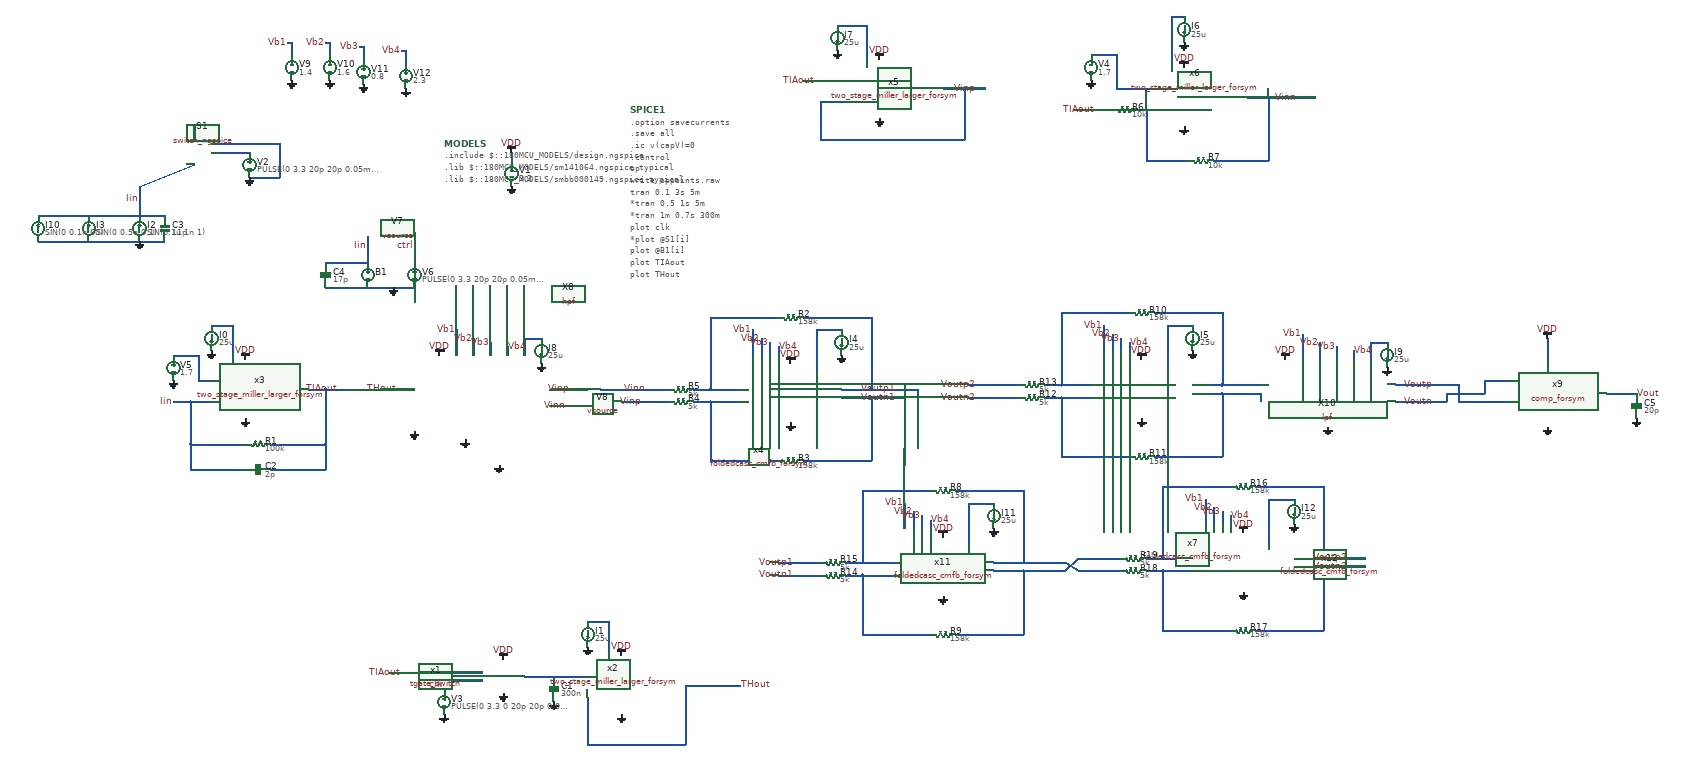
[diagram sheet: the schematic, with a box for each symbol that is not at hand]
v {xschem version=3.4.8RC file_version=1.3}
G {}
K {}
V {}
S {}
F {}
E {}
N 870 110 940 110 {lab=#net1
}
N 940 110 1020 110 {lab=#net1
}
N 1020 160 1020 270 {lab=THout
}
N 1250 130 1250 270 {lab=THout
}
N 1020 270 1250 270 {lab=THout
}
N 680 100 770 100 {lab=TIAout
}
N 680 120 770 120 {lab=clk
}
N 840 -1130 840 -1110 {lab=VDD}
N 680 120 680 140 {lab=clk
}
N 550 100 680 100 {lab=TIAout
}
N 360 -570 400 -570 {lab=TIAout
}
N 130 -720 180 -720 {lab=#net2
}
N 180 -720 180 -650 {lab=#net2
}
N 400 -570 400 -440 {lab=TIAout
}
N 80 -540 80 -440 {lab=Iin
}
N 80 -540 130 -540 {lab=Iin
}
N 270 -440 400 -440 {lab=TIAout
}
N 80 -440 210 -440 {lab=Iin
}
N 270 -380 400 -380 {lab=TIAout
}
N 400 -440 400 -380 {lab=TIAout
}
N 80 -380 210 -380 {lab=Iin
}
N 80 -440 80 -380 {lab=Iin
}
N 400 -570 450 -570 {lab=TIAout
}
N 40 -540 80 -540 {lab=Iin
}
N 40 -650 100 -650 {lab=#net3
}
N 100 -650 100 -590 {lab=#net3
}
N 100 -590 130 -590 {lab=#net3
}
N -40 -1010 -40 -980 {lab=Iin
spice_ignore=true}
N -40 -980 20 -980 {lab=Iin
spice_ignore=true}
N -40 -920 20 -920 {lab=0
spice_ignore=true}
N 1250 130 1380 130 {lab=THout
}
N 1020 -20 1070 -20 {lab=#net4
}
N 1070 -20 1070 50 {lab=#net4
}
N -40 -1050 -40 -1010 {lab=Iin
spice_ignore=true}
N 130 -1130 220 -1130 {lab=#net3
spice_ignore=true}
N 130 -1150 290 -1150 {lab=0
spice_ignore=true}
N 220 -1070 290 -1070 {lab=0
spice_ignore=true}
N 290 -1150 290 -1070 {lab=0
spice_ignore=true}
N -160 -980 -40 -980 {lab=Iin
spice_ignore=true}
N -160 -920 -40 -920 {lab=0
spice_ignore=true}
N -40 -1050 90 -1100 {lab=Iin
spice_ignore=true}
N 90 -1190 90 -1160 {lab=#net4
spice_ignore=true}
N 1620 -550 1690 -550 {lab=Voutn1
}
N 1690 -550 1690 -400 {lab=Voutn1
}
N 1310 -540 1380 -540 {lab=#net5
}
N 1310 -570 1380 -570 {lab=#net6
}
N 1310 -740 1310 -590 {lab=#net6
}
N 1620 -570 1690 -570 {lab=Voutp1
}
N 1690 -740 1690 -570 {lab=Voutp1
}
N 1690 -570 1800 -570 {lab=Voutp1
}
N 1690 -550 1770 -550 {lab=Voutn1
}
N 1410 -710 1410 -650 {lab=Vb1
}
N 1430 -690 1430 -650 {lab=Vb2
}
N 1530 -740 1690 -740 {lab=Voutp1
}
N 1310 -740 1470 -740 {lab=#net6
}
N 1530 -400 1690 -400 {lab=Voutn1
}
N 1310 -400 1470 -400 {lab=#net5
}
N 1270 -570 1310 -570 {lab=#net6
}
N 1270 -540 1310 -540 {lab=#net5
}
N 1310 -590 1310 -570 {lab=#net6
}
N 1310 -540 1310 -400 {lab=#net5
}
N 1450 -680 1450 -650 {lab=Vb3
}
N 1470 -670 1470 -650 {lab=Vb4
}
N 1560 -710 1560 -610 {lab=#net7
}
N 1560 -710 1620 -710 {lab=#net7
}
N 1800 -570 1800 -550 {lab=Voutp1
}
N 1770 -580 1770 -550 {lab=Voutn1
}
N 2450 -560 2520 -560 {lab=#net8
}
N 2520 -560 2520 -410 {lab=#net8
}
N 2140 -550 2210 -550 {lab=#net9
}
N 2140 -580 2210 -580 {lab=#net10
}
N 2140 -750 2140 -600 {lab=#net10
}
N 2450 -580 2520 -580 {lab=#net11
}
N 2520 -750 2520 -580 {lab=#net11
}
N 2240 -720 2240 -660 {lab=Vb1
}
N 2260 -700 2260 -660 {lab=Vb2
}
N 2360 -750 2520 -750 {lab=#net11
}
N 2140 -750 2300 -750 {lab=#net10
}
N 2360 -410 2520 -410 {lab=#net8
}
N 2140 -410 2300 -410 {lab=#net9
}
N 2100 -580 2140 -580 {lab=#net10
}
N 2100 -550 2140 -550 {lab=#net9
}
N 2000 -550 2040 -550 {lab=Voutn2
}
N 2140 -600 2140 -580 {lab=#net10
}
N 2140 -550 2140 -410 {lab=#net9
}
N 2280 -690 2280 -660 {lab=Vb3
}
N 2300 -680 2300 -660 {lab=Vb4
}
N 2390 -720 2390 -620 {lab=#net12
}
N 2390 -720 2450 -720 {lab=#net12
}
N 2000 -580 2040 -580 {lab=Voutp2
}
N 2520 -580 2610 -580 {lab=#net11
}
N 2520 -560 2610 -560 {lab=#net8
}
N 1920 -580 2000 -580 {lab=Voutp2
}
N 1920 -550 2000 -550 {lab=Voutn2
}
N 320 -1390 320 -1360 {lab=Vb1
}
N 310 -1390 320 -1390 {lab=Vb1
}
N 410 -1390 410 -1360 {lab=Vb2
}
N 400 -1390 410 -1390 {lab=Vb2
}
N 490 -1380 490 -1350 {lab=Vb3
}
N 480 -1380 490 -1380 {lab=Vb3
}
N 590 -1370 590 -1340 {lab=Vb4
}
N 580 -1370 590 -1370 {lab=Vb4
}
N 1530 -1300 1630 -1300 {lab=TIAout
spice_ignore=true}
N 1570 -1250 1630 -1250 {lab=Vinp
spice_ignore=true}
N 1570 -1250 1570 -1160 {lab=Vinp
spice_ignore=true}
N 1570 -1160 1910 -1160 {lab=Vinp
spice_ignore=true}
N 1910 -1280 1910 -1160 {lab=Vinp
spice_ignore=true}
N 1860 -1280 1910 -1280 {lab=Vinp
spice_ignore=true}
N 2580 -1260 2740 -1260 {lab=Vinn
spice_ignore=true}
N 1610 -1430 1680 -1430 {lab=#net11
spice_ignore=true}
N 1680 -1430 1680 -1350 {lab=#net11
spice_ignore=true}
N 2400 -1450 2400 -1340 {lab=#net12
spice_ignore=true}
N 2400 -1450 2430 -1450 {lab=#net12
spice_ignore=true}
N 1910 -1280 1960 -1280 {lab=Vinp
spice_ignore=true}
N 2310 -1280 2350 -1280 {lab=#net13
spice_ignore=true}
N 2310 -1230 2350 -1230 {lab=#net14
spice_ignore=true}
N 2270 -1280 2310 -1280 {lab=#net13
spice_ignore=true}
N 2630 -1260 2630 -1110 {lab=Vinn
spice_ignore=true}
N 2500 -1110 2630 -1110 {lab=Vinn
spice_ignore=true}
N 2340 -1110 2440 -1110 {lab=#net14
spice_ignore=true}
N 2340 -1230 2340 -1110 {lab=#net14
spice_ignore=true}
N 2170 -1230 2260 -1230 {lab=TIAout
spice_ignore=true}
N 2210 -1360 2270 -1360 {lab=#net13
spice_ignore=true}
N 2270 -1360 2270 -1280 {lab=#net13
spice_ignore=true}
N 1100 -570 1210 -570 {lab=Vinn
}
N 1100 -540 1210 -540 {lab=Vinp
}
N 500 -810 610 -810 {lab=0
}
N 610 -940 610 -870 {lab=ctrl
}
N 500 -930 500 -870 {lab=Iin
}
N 400 -870 500 -870 {lab=Iin
}
N 400 -810 500 -810 {lab=0
}
N 1050 -570 1100 -570 {lab=Vinn}
N 2930 -580 2980 -580 {lab=Voutp}
N 2930 -540 2980 -540 {lab=Voutn}
N 2980 -580 3050 -580 {lab=Voutp}
N 2980 -540 3050 -540 {lab=Voutn}
N 3290 -690 3290 -630 {lab=VDD}
N 3430 -560 3500 -560 {lab=Vout}
N 3140 -590 3200 -590 {lab=Voutn}
N 3120 -540 3200 -540 {lab=Voutp}
N 3140 -590 3140 -570 {lab=Voutn}
N 3080 -540 3120 -540 {lab=Voutp}
N 3050 -580 3080 -580 {lab=Voutp}
N 3080 -580 3080 -540 {lab=Voutp}
N 3050 -560 3050 -540 {lab=Voutn}
N 3050 -560 3140 -560 {lab=Voutn}
N 3140 -570 3140 -560 {lab=Voutn}
N 530 -570 610 -570 {lab=THout}
N 930 -570 1020 -570 {lab=Vinp}
N 930 -530 1010 -530 {lab=Vinn}
N 710 -710 710 -650 {lab=Vb1
}
N 750 -690 750 -650 {lab=Vb2
}
N 790 -680 790 -650 {lab=Vb3
}
N 830 -670 830 -650 {lab=Vb4
}
N 870 -690 870 -650 {lab=#net13}
N 870 -690 910 -690 {lab=#net13}
N 2610 -560 2610 -540 {lab=#net8}
N 2710 -700 2710 -640 {lab=Vb1
}
N 2750 -680 2750 -640 {lab=Vb2
}
N 2790 -670 2790 -640 {lab=Vb3
}
N 2830 -660 2830 -640 {lab=Vb4
}
N 2870 -680 2870 -640 {lab=#net14}
N 2870 -680 2910 -680 {lab=#net14}
N -280 -980 -160 -980 {lab=Iin
spice_ignore=true}
N -280 -920 -160 -920 {lab=0
spice_ignore=true}
N 1980 -140 2050 -140 {lab=#net15
}
N 2050 -140 2050 10 {lab=#net15
}
N 1670 -130 1740 -130 {lab=#net16
}
N 1670 -160 1740 -160 {lab=#net17
}
N 1670 -330 1670 -180 {lab=#net17
}
N 1980 -160 2050 -160 {lab=#net18
}
N 2050 -330 2050 -160 {lab=#net18
}
N 1770 -300 1770 -240 {lab=Vb1
}
N 1790 -280 1790 -240 {lab=Vb2
}
N 1890 -330 2050 -330 {lab=#net18
}
N 1670 -330 1830 -330 {lab=#net17
}
N 1890 10 2050 10 {lab=#net15
}
N 1670 10 1830 10 {lab=#net16
}
N 1630 -160 1670 -160 {lab=#net17
}
N 1630 -130 1670 -130 {lab=#net16
}
N 1670 -180 1670 -160 {lab=#net17
}
N 1670 -130 1670 10 {lab=#net16
}
N 1810 -270 1810 -240 {lab=Vb3
}
N 1830 -260 1830 -240 {lab=Vb4
}
N 1920 -300 1920 -200 {lab=#net19
}
N 1920 -300 1980 -300 {lab=#net19
}
N 2050 -160 2150 -160 {lab=#net18}
N 2050 -140 2150 -140 {lab=#net15}
N 1470 -160 1570 -160 {lab=Voutp1}
N 1470 -130 1570 -130 {lab=Voutn1}
N 2690 -150 2760 -150 {lab=Voutn2
}
N 2760 -150 2760 0 {lab=Voutn2
}
N 2380 -140 2450 -140 {lab=#net20
}
N 2380 -170 2450 -170 {lab=#net21
}
N 2380 -340 2380 -190 {lab=#net21
}
N 2690 -170 2760 -170 {lab=Voutp2
}
N 2760 -340 2760 -170 {lab=Voutp2
}
N 2480 -310 2480 -250 {lab=Vb1
}
N 2500 -290 2500 -250 {lab=Vb2
}
N 2600 -340 2760 -340 {lab=Voutp2
}
N 2380 -340 2540 -340 {lab=#net21
}
N 2600 0 2760 0 {lab=Voutn2
}
N 2380 0 2540 0 {lab=#net20
}
N 2340 -170 2380 -170 {lab=#net21
}
N 2340 -140 2380 -140 {lab=#net20
}
N 2380 -190 2380 -170 {lab=#net21
}
N 2380 -140 2380 0 {lab=#net20
}
N 2520 -280 2520 -250 {lab=Vb3
}
N 2540 -270 2540 -250 {lab=Vb4
}
N 2630 -310 2630 -210 {lab=#net22
}
N 2630 -310 2690 -310 {lab=#net22
}
N 2760 -170 2860 -170 {lab=Voutp2}
N 2760 -150 2860 -150 {lab=Voutn2}
N 2180 -170 2280 -170 {lab=#net15}
N 2180 -140 2280 -140 {lab=#net18}
N 2150 -160 2180 -140 {lab=#net18}
N 2150 -140 2180 -170 {lab=#net15}
C {capa.sym} 940 140 0 0 {name=C1
m=1
value=300n
footprint=1206
device="ceramic capacitor"
}
C {gnd.sym} 1100 200 0 0 {name=l1 lab=0
}
C {gnd.sym} 940 170 0 0 {name=l2 lab=0
}
C {gnd.sym} 820 150 0 0 {name=l3 lab=0
}
C {vdd.sym} 1100 60 0 0 {name=l4 lab=VDD
}
C {vdd.sym} 820 70 0 0 {name=l5 lab=VDD
}
C {chipathon-2026-ppg/jz_tia/two_stage_miller_larger_forsym.sym} 1100 130 0 0 {name=x2
}
C {chipathon-2026-ppg/jz_trackhold/tgate_switch.sym} 890 120 0 0 {name=x1
}
C {code.sym} 680 -1150 0 0 {name=MODELS only_toplevel=true  
format="tcleval( @value )" 
value="
.include $::180MCU_MODELS/design.ngspice
.lib $::180MCU_MODELS/sm141064.ngspice typical
.lib $::180MCU_MODELS/smbb000149.ngspice typical
"}
C {vsource.sym} 840 -1080 0 0 {name=V1 value=3.3 savecurrent=false}
C {vdd.sym} 840 -1130 0 0 {name=l6 lab=VDD}
C {gnd.sym} 840 -1050 0 0 {name=l11 lab=0}
C {code_shown.sym} 1120 -1230 0 0 {name=SPICE1 only_toplevel=false value=".option savecurrents
.save all
.ic v(capV)=0
.control
op
write oppoints.raw
tran 0.1 3s 5m
*tran 0.5 1s 5m
*tran 1m 0.7s 300m
plot clk
*plot @S1[i]
plot @B1[i]
plot TIAout
plot THout
plot Vinp Vinn
plot Voutp1 Voutn1
plot Voutp Voutn
plot Vout
.endc"
}
C {vsource.sym} 680 170 0 0 {name=V3 value="PULSE(0 3.3 0 20p 20p 0.05m 0.5m)" savecurrent=false
}
C {gnd.sym} 680 200 0 0 {name=l7 lab=0
}
C {isource.sym} 130 -690 0 0 {name=I0 value=25u
}
C {gnd.sym} 130 -660 0 0 {name=l9 lab=0
}
C {vdd.sym} 210 -640 0 0 {name=l10 lab=VDD
}
C {gnd.sym} 210 -500 0 0 {name=l12 lab=0
}
C {lab_pin.sym} 40 -540 0 0 {name=p1 sig_type=std_logic lab=Iin
spice_ignore=short}
C {res.sym} 240 -440 1 0 {name=R1
value=100k
footprint=1206
device=resistor
m=1
}
C {capa.sym} 240 -380 1 0 {name=C2
m=1
value=2p
footprint=1206
device="ceramic capacitor"
}
C {gnd.sym} 2210 -1300 0 0 {name=l13 lab=0
spice_ignore=true}
C {vsource.sym} 2210 -1330 0 0 {name=V4 value=1.7 savecurrent=false
spice_ignore=true}
C {chipathon-2026-ppg/jz_tia/two_stage_miller_larger_forsym.sym} 210 -570 0 0 {name=x3
}
C {gnd.sym} -40 -920 0 0 {name=l31 lab=0
spice_ignore=true}
C {lab_pin.sym} -40 -1020 0 0 {name=p11 sig_type=std_logic lab=Iin
spice_ignore=true}
C {capa.sym} 20 -950 0 0 {name=C3
m=1
value=11p
footprint=1206
device="ceramic capacitor"
spice_ignore=true}
C {isource.sym} -40 -950 2 0 {name=I2 value="SIN(0.1u 1n 1)"
spice_ignore=true}
C {lab_pin.sym} 430 -570 1 0 {name=p2 sig_type=std_logic lab=TIAout
}
C {lab_pin.sym} 1380 130 2 0 {name=p3 sig_type=std_logic lab=THout
}
C {isource.sym} 1020 10 0 0 {name=I1 value=25u
}
C {gnd.sym} 1020 40 0 0 {name=l8 lab=0
}
C {lab_pin.sym} 680 130 0 0 {name=p5 sig_type=std_logic lab=clk
}
C {vsource.sym} 220 -1100 0 0 {name=V2 value="PULSE(0 3.3 20p 20p 0.05m 0.5m)" savecurrent=false
spice_ignore=true}
C {gnd.sym} 220 -1070 0 0 {name=l14 lab=0
spice_ignore=true}
C {isource.sym} -160 -950 2 0 {name=I3 value="SIN(0 0.5n 0.1)"
spice_ignore=true}
C {switch_ngspice.sym} 90 -1130 2 0 {name=S1 model=SW1
device_model=".MODEL SW1 SW 
+ VT=0.9 VH=0.01
+ RON=1 ROFF=10e6 "
spice_ignore=true}
C {lab_pin.sym} 1430 -690 3 1 {name=p6 sig_type=std_logic lab=Vb2
}
C {lab_pin.sym} 1410 -710 0 0 {name=p7 sig_type=std_logic lab=Vb1
}
C {vdd.sym} 1500 -630 0 0 {name=l15 lab=VDD
}
C {isource.sym} 1620 -680 0 0 {name=I4 value=25u
}
C {gnd.sym} 1500 -490 0 0 {name=l16 lab=0
}
C {res.sym} 1500 -740 1 0 {name=R2
value=158k
footprint=1206
device=resistor
m=1
}
C {res.sym} 1500 -400 1 0 {name=R3
value=158k
footprint=1206
device=resistor
m=1
}
C {res.sym} 1240 -540 1 0 {name=R4
value=5k
footprint=1206
device=resistor
m=1
}
C {res.sym} 1240 -570 1 0 {name=R5
value=5k
footprint=1206
device=resistor
m=1
}
C {chipathon-2026-ppg/jz_fda2/foldedcasc_cmfb_forsym.sym} 1510 -360 0 0 {name=x4
}
C {lab_pin.sym} 1470 -670 0 1 {name=p8 sig_type=std_logic lab=Vb4
}
C {lab_pin.sym} 1450 -680 3 1 {name=p9 sig_type=std_logic lab=Vb3
}
C {gnd.sym} 1620 -650 0 0 {name=l17 lab=0
}
C {lab_pin.sym} 2260 -700 3 1 {name=p24 sig_type=std_logic lab=Vb2
}
C {lab_pin.sym} 2240 -720 0 0 {name=p25 sig_type=std_logic lab=Vb1
}
C {vdd.sym} 2330 -640 0 0 {name=l24 lab=VDD
}
C {isource.sym} 2450 -690 0 0 {name=I5 value=25u
}
C {gnd.sym} 2330 -500 0 0 {name=l25 lab=0
}
C {res.sym} 2330 -750 1 0 {name=R10
value=158k
footprint=1206
device=resistor
m=1
}
C {res.sym} 2330 -410 1 0 {name=R11
value=158k
footprint=1206
device=resistor
m=1
}
C {res.sym} 2070 -550 1 0 {name=R12
value=5k
footprint=1206
device=resistor
m=1
}
C {res.sym} 2070 -580 1 0 {name=R13
value=5k
footprint=1206
device=resistor
m=1
}
C {chipathon-2026-ppg/jz_fda2/foldedcasc_cmfb_forsym.sym} 2340 -370 0 0 {name=x7
}
C {lab_pin.sym} 2300 -680 0 1 {name=p26 sig_type=std_logic lab=Vb4
}
C {lab_pin.sym} 2280 -690 3 1 {name=p27 sig_type=std_logic lab=Vb3
}
C {gnd.sym} 2450 -660 0 0 {name=l26 lab=0
}
C {vsource.sym} 320 -1330 0 0 {name=V9 value=1.4 savecurrent=false
}
C {gnd.sym} 320 -1300 0 0 {name=l18 lab=0
}
C {lab_pin.sym} 310 -1390 0 0 {name=p14 sig_type=std_logic lab=Vb1
}
C {vsource.sym} 410 -1330 0 0 {name=V10 value=1.6 savecurrent=false
}
C {gnd.sym} 410 -1300 0 0 {name=l19 lab=0
}
C {lab_pin.sym} 400 -1390 0 0 {name=p15 sig_type=std_logic lab=Vb2
}
C {vsource.sym} 490 -1320 0 0 {name=V11 value=0.8 savecurrent=false
}
C {gnd.sym} 490 -1290 0 0 {name=l20 lab=0
}
C {lab_pin.sym} 480 -1380 0 0 {name=p16 sig_type=std_logic lab=Vb3
}
C {vsource.sym} 590 -1310 0 0 {name=V12 value=2.3 savecurrent=false
}
C {gnd.sym} 590 -1280 0 0 {name=l21 lab=0
}
C {lab_pin.sym} 580 -1370 0 0 {name=p17 sig_type=std_logic lab=Vb4
}
C {chipathon-2026-ppg/jz_tia/two_stage_miller_larger_forsym.sym} 1710 -1280 0 0 {name=x5
spice_ignore=true}
C {chipathon-2026-ppg/jz_tia/two_stage_miller_larger_forsym.sym} 2430 -1260 0 0 {name=x6
spice_ignore=true}
C {gnd.sym} 1710 -1210 0 0 {name=l22 lab=0
spice_ignore=true}
C {gnd.sym} 2430 -1190 0 0 {name=l23 lab=0
spice_ignore=true}
C {isource.sym} 2430 -1420 0 0 {name=I6 value=25u
spice_ignore=true}
C {gnd.sym} 2430 -1390 0 0 {name=l27 lab=0
spice_ignore=true}
C {vdd.sym} 1710 -1350 0 0 {name=l28 lab=VDD
spice_ignore=true}
C {vdd.sym} 2430 -1330 0 0 {name=l29 lab=VDD
spice_ignore=true}
C {lab_pin.sym} 1560 -1300 1 0 {name=p10 sig_type=std_logic lab=TIAout
spice_ignore=true}
C {lab_pin.sym} 2700 -1260 1 0 {name=p12 sig_type=std_logic lab=Vinn
spice_ignore=true}
C {lab_pin.sym} 2220 -1230 3 0 {name=p13 sig_type=std_logic lab=TIAout
spice_ignore=true}
C {lab_pin.sym} 1940 -1280 1 0 {name=p18 sig_type=std_logic lab=Vinp
spice_ignore=true}
C {isource.sym} 1610 -1400 0 0 {name=I7 value=25u
spice_ignore=true}
C {gnd.sym} 1610 -1370 0 0 {name=l30 lab=0
spice_ignore=true}
C {res.sym} 2290 -1230 1 0 {name=R6
value=10k
footprint=1206
device=resistor
m=1
spice_ignore=true}
C {res.sym} 2470 -1110 1 0 {name=R7
value=10k
footprint=1206
device=resistor
m=1
spice_ignore=true}
C {lab_pin.sym} 570 -570 1 0 {name=p19 sig_type=std_logic lab=THout
}
C {lab_pin.sym} 1160 -570 1 0 {name=p20 sig_type=std_logic lab=Vinn
}
C {lab_pin.sym} 3020 -580 1 0 {name=p21 sig_type=std_logic lab=Voutp
}
C {lab_pin.sym} 3020 -540 3 0 {name=p22 sig_type=std_logic lab=Voutn
}
C {gnd.sym} 40 -590 0 0 {name=l32 lab=0
}
C {vsource.sym} 40 -620 0 0 {name=V5 value=1.7 savecurrent=false
}
C {lab_pin.sym} 580 100 1 0 {name=p23 sig_type=std_logic lab=TIAout
}
C {bsource.sym} 500 -840 0 0 {name=B1 VAR=I FUNC="(0.1u + 1n * sin(2*pi*1*time)) * (v(ctrl) > 1.65 ? 1 : 0)" m=1
}
C {vsource.sym} 610 -840 0 0 {name=V6 value="PULSE(0 3.3 20p 20p 0.05m 0.5m)" savecurrent=false
}
C {gnd.sym} 560 -810 0 0 {name=l33 lab=0
}
C {lab_pin.sym} 500 -910 0 0 {name=p28 sig_type=std_logic lab=Iin
}
C {lab_pin.sym} 610 -910 0 0 {name=p29 sig_type=std_logic lab=ctrl
}
C {capa.sym} 400 -840 0 0 {name=C4
m=1
value=17p
footprint=1206
device="ceramic capacitor"
}
C {gnd.sym} 610 -470 0 0 {name=l34 lab=0
}
C {vsource.sym} 610 -500 0 0 {name=V7 value=1.7 savecurrent=false
}
C {lab_pin.sym} 1750 -570 1 0 {name=p30 sig_type=std_logic lab=Voutp1
}
C {lab_pin.sym} 1750 -550 3 0 {name=p31 sig_type=std_logic lab=Voutn1
}
C {chipathon-2026-ppg/ps-filters/hpf.sym} 770 -550 0 0 {name=X8}
C {gnd.sym} 810 -390 0 0 {name=l35 lab=0
}
C {vsource.sym} 810 -420 0 0 {name=V8 value=1.7 savecurrent=false
}
C {chipathon-2026-ppg/comparator/schematic-design/comp_forsym.sym} 3300 -560 0 0 {name=x9}
C {gnd.sym} 3290 -480 0 0 {name=l36 lab=0
}
C {lab_pin.sym} 3500 -560 0 1 {name=p32 sig_type=std_logic lab=Vout
}
C {vdd.sym} 3290 -690 0 0 {name=l37 lab=VDD}
C {lab_pin.sym} 980 -570 1 0 {name=p33 sig_type=std_logic lab=Vinp
}
C {lab_pin.sym} 970 -530 3 0 {name=p34 sig_type=std_logic lab=Vinn
}
C {lab_pin.sym} 1150 -540 3 0 {name=p35 sig_type=std_logic lab=Vinp
}
C {gnd.sym} 730 -450 0 0 {name=l38 lab=0
}
C {vdd.sym} 670 -650 0 0 {name=l39 lab=VDD
}
C {isource.sym} 910 -660 0 0 {name=I8 value=25u
}
C {gnd.sym} 910 -630 0 0 {name=l40 lab=0
}
C {lab_pin.sym} 710 -710 0 0 {name=p4 sig_type=std_logic lab=Vb1
}
C {lab_pin.sym} 750 -690 3 1 {name=p36 sig_type=std_logic lab=Vb2
}
C {lab_pin.sym} 790 -680 3 1 {name=p37 sig_type=std_logic lab=Vb3
}
C {lab_pin.sym} 830 -670 0 1 {name=p38 sig_type=std_logic lab=Vb4
}
C {chipathon-2026-ppg/ps-filters/lpf.sym} 2770 -560 0 0 {name=X10}
C {vdd.sym} 2670 -640 0 0 {name=l41 lab=VDD
}
C {isource.sym} 2910 -650 0 0 {name=I9 value=25u
}
C {lab_pin.sym} 2710 -700 0 0 {name=p39 sig_type=std_logic lab=Vb1
}
C {lab_pin.sym} 2750 -680 3 1 {name=p40 sig_type=std_logic lab=Vb2
}
C {lab_pin.sym} 2790 -670 3 1 {name=p41 sig_type=std_logic lab=Vb3
}
C {lab_pin.sym} 2830 -660 0 1 {name=p42 sig_type=std_logic lab=Vb4
}
C {gnd.sym} 2770 -480 0 0 {name=l42 lab=0
}
C {gnd.sym} 2910 -620 0 0 {name=l43 lab=0
}
C {isource.sym} -280 -950 2 0 {name=I10 value="SIN(0 0.1n 60)"
spice_ignore=true}
C {capa.sym} 3500 -530 0 0 {name=C5
m=1
value=20p
footprint=1206
device="ceramic capacitor"
}
C {gnd.sym} 3500 -500 0 0 {name=l44 lab=0
}
C {lab_pin.sym} 1790 -280 3 1 {name=p43 sig_type=std_logic lab=Vb2
}
C {lab_pin.sym} 1770 -300 0 0 {name=p44 sig_type=std_logic lab=Vb1
}
C {vdd.sym} 1860 -220 0 0 {name=l45 lab=VDD
}
C {isource.sym} 1980 -270 0 0 {name=I11 value=25u
}
C {gnd.sym} 1860 -80 0 0 {name=l46 lab=0
}
C {res.sym} 1860 -330 1 0 {name=R8
value=158k
footprint=1206
device=resistor
m=1
}
C {res.sym} 1860 10 1 0 {name=R9
value=158k
footprint=1206
device=resistor
m=1
}
C {res.sym} 1600 -130 1 0 {name=R14
value=5k
footprint=1206
device=resistor
m=1
}
C {res.sym} 1600 -160 1 0 {name=R15
value=5k
footprint=1206
device=resistor
m=1
}
C {chipathon-2026-ppg/jz_fda2/foldedcasc_cmfb_forsym.sym} 1870 50 0 0 {name=x11
}
C {lab_pin.sym} 1830 -260 0 1 {name=p45 sig_type=std_logic lab=Vb4
}
C {lab_pin.sym} 1810 -270 3 1 {name=p46 sig_type=std_logic lab=Vb3
}
C {gnd.sym} 1980 -240 0 0 {name=l47 lab=0
}
C {lab_pin.sym} 1940 -580 1 0 {name=p47 sig_type=std_logic lab=Voutp2
}
C {lab_pin.sym} 1510 -160 1 0 {name=p50 sig_type=std_logic lab=Voutp1
}
C {lab_pin.sym} 1510 -130 3 0 {name=p51 sig_type=std_logic lab=Voutn1
}
C {lab_pin.sym} 1940 -550 3 0 {name=p52 sig_type=std_logic lab=Voutn2
}
C {lab_pin.sym} 2500 -290 3 1 {name=p53 sig_type=std_logic lab=Vb2
}
C {lab_pin.sym} 2480 -310 0 0 {name=p54 sig_type=std_logic lab=Vb1
}
C {vdd.sym} 2570 -230 0 0 {name=l48 lab=VDD
}
C {isource.sym} 2690 -280 0 0 {name=I12 value=25u
}
C {gnd.sym} 2570 -90 0 0 {name=l49 lab=0
}
C {res.sym} 2570 -340 1 0 {name=R16
value=158k
footprint=1206
device=resistor
m=1
}
C {res.sym} 2570 0 1 0 {name=R17
value=158k
footprint=1206
device=resistor
m=1
}
C {res.sym} 2310 -140 1 0 {name=R18
value=5k
footprint=1206
device=resistor
m=1
}
C {res.sym} 2310 -170 1 0 {name=R19
value=5k
footprint=1206
device=resistor
m=1
}
C {chipathon-2026-ppg/jz_fda2/foldedcasc_cmfb_forsym.sym} 2580 40 0 0 {name=x12
}
C {lab_pin.sym} 2540 -270 0 1 {name=p55 sig_type=std_logic lab=Vb4
}
C {lab_pin.sym} 2520 -280 3 1 {name=p56 sig_type=std_logic lab=Vb3
}
C {gnd.sym} 2690 -250 0 0 {name=l50 lab=0
}
C {lab_pin.sym} 2820 -170 1 0 {name=p57 sig_type=std_logic lab=Voutp2
}
C {lab_pin.sym} 2820 -150 3 0 {name=p58 sig_type=std_logic lab=Voutn2
}
